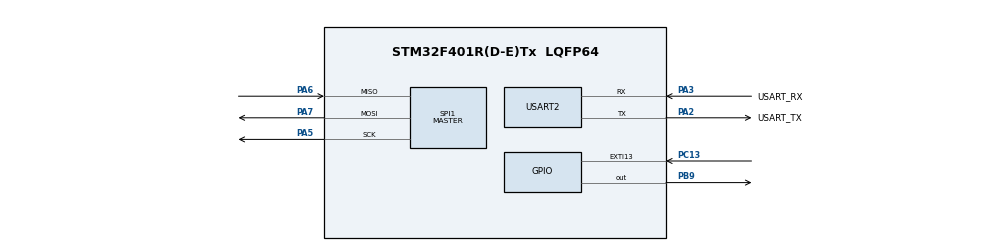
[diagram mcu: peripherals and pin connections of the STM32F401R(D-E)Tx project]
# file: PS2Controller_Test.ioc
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Mcu.Family=STM32F4
Mcu.Name=STM32F401R(D-E)Tx
Mcu.Package=LQFP64
NVIC.EXTI15_10_IRQn=true\:1\:1\:true\:false\:true\:true\:true\:true
NVIC.PriorityGroup=NVIC_PRIORITYGROUP_1
NVIC.SPI1_IRQn=true\:0\:0\:false\:false\:true\:true\:true\:true
PA13.GPIO_Label=TMS
PA13.Mode=Serial_Wire
PA13.Signal=SYS_JTMS-SWDIO
PA14.GPIO_Label=TCK
PA14.Mode=Serial_Wire
PA14.Signal=SYS_JTCK-SWCLK
PA2.GPIO_Label=USART_TX
PA2.GPIO_Mode=GPIO_MODE_AF_PP
PA2.GPIO_PuPd=GPIO_NOPULL
PA2.GPIO_Speed=GPIO_SPEED_FREQ_LOW
PA2.Mode=Asynchronous
PA2.Signal=USART2_TX
PA3.GPIO_Label=USART_RX
PA3.GPIO_Mode=GPIO_MODE_AF_PP
PA3.GPIO_PuPd=GPIO_NOPULL
PA3.GPIO_Speed=GPIO_SPEED_FREQ_LOW
PA3.Mode=Asynchronous
PA3.Signal=USART2_RX
PA5.Mode=Full_Duplex_Master
PA5.Signal=SPI1_SCK
PA6.Mode=Full_Duplex_Master
PA6.Signal=SPI1_MISO
PA7.Mode=Full_Duplex_Master
PA7.Signal=SPI1_MOSI
PB3.GPIO_Label=SWO
PB3.Signal=SYS_JTDO-SWO
PB9.Signal=GPIO_Output
PC13-ANTI_TAMP.Signal=GPXTI13
PC14-OSC32_IN.Mode=LSE-External-Oscillator
PC14-OSC32_IN.Signal=RCC_OSC32_IN
PC15-OSC32_OUT.Mode=LSE-External-Oscillator
PC15-OSC32_OUT.Signal=RCC_OSC32_OUT
PH0\ -\ OSC_IN.Mode=HSE-External-Clock-Source
PH0\ -\ OSC_IN.Signal=RCC_OSC_IN
PH1\ -\ OSC_OUT.Mode=HSE-External-Clock-Source
PH1\ -\ OSC_OUT.Signal=RCC_OSC_OUT
ProjectManager.HeapSize=0x200
ProjectManager.StackSize=0x400
ProjectManager.TargetToolchain=STM32CubeIDE
RCC.48MHZClocksFreq_Value=18285714.285714287
RCC.AHBCLKDivider=RCC_SYSCLK_DIV16
RCC.AHBFreq_Value=4000000
RCC.APB1CLKDivider=RCC_HCLK_DIV2
RCC.APB1Freq_Value=2000000
RCC.APB1TimFreq_Value=4000000
RCC.APB2Freq_Value=4000000
RCC.APB2TimFreq_Value=4000000
RCC.CortexFreq_Value=4000000
RCC.HCLKFreq_Value=4000000
RCC.HSE_VALUE=8000000
RCC.HSI_VALUE=16000000
RCC.PLLM=8
RCC.PLLN=64
RCC.PLLQ=7
RCC.SYSCLKFreq_VALUE=64000000
RCC.SYSCLKSource=RCC_SYSCLKSOURCE_PLLCLK
RCC.VCOOutputFreq_Value=128000000
SPI1.BaudRatePrescaler=SPI_BAUDRATEPRESCALER_256
SPI1.Direction=SPI_DIRECTION_2LINES
SPI1.FirstBit=SPI_FIRSTBIT_LSB
SPI1.Mode=SPI_MODE_MASTER
SPI1.VirtualType=VM_MASTER
USART2.VirtualMode=VM_ASYNC
board=NUCLEO-F401RE

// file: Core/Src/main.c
/* USER CODE BEGIN Header */
/**
  ******************************************************************************
  * @file           : main.c
  * @brief          : Main program body
  ******************************************************************************
  * @attention
  *
  * Copyright (c) 2023 STMicroelectronics.
  * All rights reserved.
  *
  * This software is licensed under terms that can be found in the LICENSE file
  * in the root directory of this software component.
  * If no LICENSE file comes with this software, it is provided AS-IS.
  *
  ******************************************************************************
  */
/* USER CODE END Header */
#include "main.h"

SPI_HandleTypeDef hspi1;

UART_HandleTypeDef huart2;

void SystemClock_Config(void);
static void MX_GPIO_Init(void);
static void MX_USART2_UART_Init(void);
static void MX_SPI1_Init(void);

/* USER CODE BEGIN 0 */

void HAL_SPI_TxRxCpltCallback(SPI_HandleTypeDef * hspi)
{

	HAL_GPIO_WritePin(GPIOB, GPIO_PIN_9, 1);
}

/* USER CODE END 0 */

int main(void)
{

  /* MCU Configuration--------------------------------------------------------*/

  /* Reset of all peripherals, Initializes the Flash interface and the Systick. */
  HAL_Init();

  /* Configure the system clock */
  SystemClock_Config();

  /* Initialize all configured peripherals */
  MX_GPIO_Init();
  MX_USART2_UART_Init();
  MX_SPI1_Init();
  /* USER CODE BEGIN 2 */

  static uint8_t header_buf[9] = {0x01, 0x42};
  static uint8_t rx_buf[9];

  	//Poll command to flush out any unwanted data
	HAL_GPIO_WritePin(GPIOB, GPIO_PIN_9, 0);
	HAL_Delay(1);
	HAL_SPI_TransmitReceive(&hspi1, header_buf, rx_buf, 5, 10);
	HAL_GPIO_WritePin(GPIOB, GPIO_PIN_9, 1);

	//Config Mode
	header_buf[1] = 0x43;
	header_buf[3] = 0x01;

	HAL_GPIO_WritePin(GPIOB, GPIO_PIN_9, 0);
	HAL_Delay(1);
	HAL_SPI_TransmitReceive(&hspi1, header_buf, rx_buf, 5, 10);
	HAL_GPIO_WritePin(GPIOB, GPIO_PIN_9, 1);

	//Turn on Analog Mode
	header_buf[1] = 0x44;
	header_buf[4] = 0x03;

	HAL_GPIO_WritePin(GPIOB, GPIO_PIN_9, 0);
	HAL_Delay(1);
	HAL_SPI_TransmitReceive(&hspi1, header_buf, rx_buf, 9, 10);
	HAL_GPIO_WritePin(GPIOB, GPIO_PIN_9, 1);

	//Turn off Config Mode
	header_buf[1] = 0x43;
	header_buf[3] = 0x00;
	header_buf[4] = 0x00;
	HAL_GPIO_WritePin(GPIOB, GPIO_PIN_9, 0);
	HAL_Delay(1);
	HAL_SPI_TransmitReceive(&hspi1, header_buf, rx_buf, 9, 10);
	HAL_GPIO_WritePin(GPIOB, GPIO_PIN_9, 1);

  //HAL_SPI_Receive(&hspi1, rx_buf, 3, 1000);

	header_buf[1] = 0x42;

  /* USER CODE END 2 */

  /* Infinite loop */
  /* USER CODE BEGIN WHILE */
  while (1)
  {

	HAL_GPIO_WritePin(GPIOB, GPIO_PIN_9, 0);
	HAL_Delay(1);
	HAL_SPI_TransmitReceive(&hspi1, header_buf, rx_buf, 9, 10);
	HAL_GPIO_WritePin(GPIOB, GPIO_PIN_9, 1);

	//uint8_t disp[] = {rx_buf[5], ' ', rx_buf[6], ' ' , rx_buf[7], ' ', rx_buf[8], '\n', '\r'};
	//HAL_UART_Transmit(&huart2, disp, sizeof(disp), 10);
	//HAL_Delay(1000);

    /* USER CODE END WHILE */

  }
}

void SystemClock_Config(void)
{
  RCC_OscInitTypeDef RCC_OscInitStruct = {0};
  RCC_ClkInitTypeDef RCC_ClkInitStruct = {0};

  /** Configure the main internal regulator output voltage
  */
  __HAL_RCC_PWR_CLK_ENABLE();
  __HAL_PWR_VOLTAGESCALING_CONFIG(PWR_REGULATOR_VOLTAGE_SCALE2);

  /** Initializes the RCC Oscillators according to the specified parameters
  * in the RCC_OscInitTypeDef structure.
  */
  RCC_OscInitStruct.OscillatorType = RCC_OSCILLATORTYPE_HSI;
  RCC_OscInitStruct.HSIState = RCC_HSI_ON;
  RCC_OscInitStruct.HSICalibrationValue = RCC_HSICALIBRATION_DEFAULT;
  RCC_OscInitStruct.PLL.PLLState = RCC_PLL_ON;
  RCC_OscInitStruct.PLL.PLLSource = RCC_PLLSOURCE_HSI;
  RCC_OscInitStruct.PLL.PLLM = 8;
  RCC_OscInitStruct.PLL.PLLN = 64;
  RCC_OscInitStruct.PLL.PLLP = RCC_PLLP_DIV2;
  RCC_OscInitStruct.PLL.PLLQ = 7;
  if (HAL_RCC_OscConfig(&RCC_OscInitStruct) != HAL_OK)
  {
    Error_Handler();
  }

  /** Initializes the CPU, AHB and APB buses clocks
  */
  RCC_ClkInitStruct.ClockType = RCC_CLOCKTYPE_HCLK|RCC_CLOCKTYPE_SYSCLK
                              |RCC_CLOCKTYPE_PCLK1|RCC_CLOCKTYPE_PCLK2;
  RCC_ClkInitStruct.SYSCLKSource = RCC_SYSCLKSOURCE_PLLCLK;
  RCC_ClkInitStruct.AHBCLKDivider = RCC_SYSCLK_DIV8;
  RCC_ClkInitStruct.APB1CLKDivider = RCC_HCLK_DIV2;
  RCC_ClkInitStruct.APB2CLKDivider = RCC_HCLK_DIV1;

  if (HAL_RCC_ClockConfig(&RCC_ClkInitStruct, FLASH_LATENCY_0) != HAL_OK)
  {
    Error_Handler();
  }
}

static void MX_SPI1_Init(void)
{

  /* SPI1 parameter configuration*/
  hspi1.Instance = SPI1;
  hspi1.Init.Mode = SPI_MODE_MASTER;
  hspi1.Init.Direction = SPI_DIRECTION_2LINES;
  hspi1.Init.DataSize = SPI_DATASIZE_8BIT;
  hspi1.Init.CLKPolarity = SPI_POLARITY_LOW;
  hspi1.Init.CLKPhase = SPI_PHASE_1EDGE;
  hspi1.Init.NSS = SPI_NSS_SOFT;
  hspi1.Init.BaudRatePrescaler = SPI_BAUDRATEPRESCALER_256;
  hspi1.Init.FirstBit = SPI_FIRSTBIT_LSB;
  hspi1.Init.TIMode = SPI_TIMODE_DISABLE;
  hspi1.Init.CRCCalculation = SPI_CRCCALCULATION_DISABLE;
  hspi1.Init.CRCPolynomial = 10;
  if (HAL_SPI_Init(&hspi1) != HAL_OK)
  {
    Error_Handler();
  }

}

static void MX_USART2_UART_Init(void)
{

  huart2.Instance = USART2;
  huart2.Init.BaudRate = 115200;
  huart2.Init.WordLength = UART_WORDLENGTH_8B;
  huart2.Init.StopBits = UART_STOPBITS_1;
  huart2.Init.Parity = UART_PARITY_NONE;
  huart2.Init.Mode = UART_MODE_TX_RX;
  huart2.Init.HwFlowCtl = UART_HWCONTROL_NONE;
  huart2.Init.OverSampling = UART_OVERSAMPLING_16;
  if (HAL_UART_Init(&huart2) != HAL_OK)
  {
    Error_Handler();
  }

}

static void MX_GPIO_Init(void)
{
  GPIO_InitTypeDef GPIO_InitStruct = {0};

  /* GPIO Ports Clock Enable */
  __HAL_RCC_GPIOC_CLK_ENABLE();
  __HAL_RCC_GPIOH_CLK_ENABLE();
  __HAL_RCC_GPIOA_CLK_ENABLE();
  __HAL_RCC_GPIOB_CLK_ENABLE();

  /*Configure GPIO pin Output Level */
  HAL_GPIO_WritePin(GPIOB, GPIO_PIN_9, GPIO_PIN_RESET);

  /*Configure GPIO pin : PC13 */
  GPIO_InitStruct.Pin = GPIO_PIN_13;
  GPIO_InitStruct.Mode = GPIO_MODE_IT_RISING;
  GPIO_InitStruct.Pull = GPIO_NOPULL;
  HAL_GPIO_Init(GPIOC, &GPIO_InitStruct);

  /*Configure GPIO pin : PB9 */
  GPIO_InitStruct.Pin = GPIO_PIN_9;
  GPIO_InitStruct.Mode = GPIO_MODE_OUTPUT_PP;
  GPIO_InitStruct.Pull = GPIO_NOPULL;
  GPIO_InitStruct.Speed = GPIO_SPEED_FREQ_LOW;
  HAL_GPIO_Init(GPIOB, &GPIO_InitStruct);

  /* EXTI interrupt init*/
  HAL_NVIC_SetPriority(EXTI15_10_IRQn, 1, 1);
  HAL_NVIC_EnableIRQ(EXTI15_10_IRQn);

}

void Error_Handler(void)
{
  __disable_irq();
  while (1)
  {
  }
}
